VERSION 5.7 ;
  NOWIREEXTENSIONATPIN ON ;
  DIVIDERCHAR "/" ;
  BUSBITCHARS "[]" ;
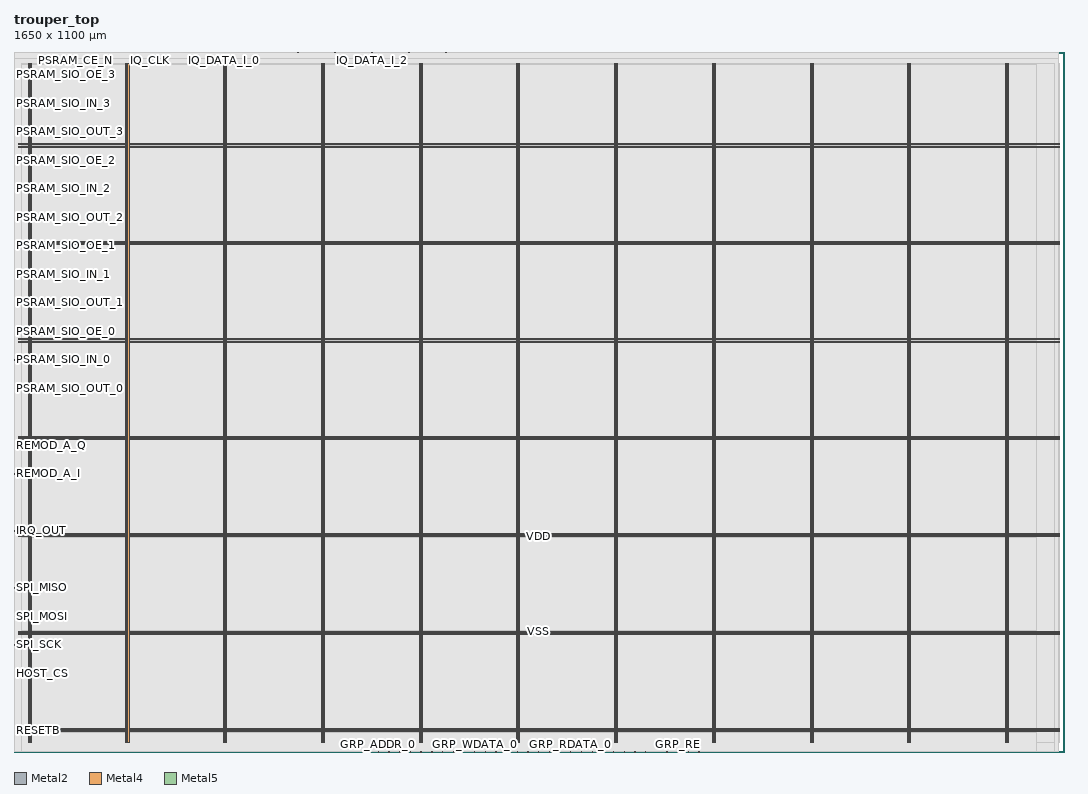
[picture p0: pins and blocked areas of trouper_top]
MACRO trouper_top
  CLASS BLOCK ;
  FOREIGN trouper_top ;
  ORIGIN 0.000 0.000 ;
  SIZE 1650.000 BY 1100.000 ;
  PIN GRP_ADDR_0
    DIRECTION INPUT ;
    USE SIGNAL ;
    ANTENNAGATEAREA 0.396000 ;
    PORT
      LAYER Metal2 ;
        RECT 572.320 0.000 572.880 0.560 ;
    END
  END GRP_ADDR_0
  PIN GRP_ADDR_1
    DIRECTION INPUT ;
    USE SIGNAL ;
    ANTENNAGATEAREA 0.396000 ;
    PORT
      LAYER Metal2 ;
        RECT 589.120 0.000 589.680 0.560 ;
    END
  END GRP_ADDR_1
  PIN GRP_ADDR_2
    DIRECTION INPUT ;
    USE SIGNAL ;
    ANTENNAGATEAREA 0.396000 ;
    PORT
      LAYER Metal2 ;
        RECT 605.920 0.000 606.480 0.560 ;
    END
  END GRP_ADDR_2
  PIN GRP_ADDR_3
    DIRECTION INPUT ;
    USE SIGNAL ;
    ANTENNAGATEAREA 0.396000 ;
    PORT
      LAYER Metal2 ;
        RECT 622.720 0.000 623.280 0.560 ;
    END
  END GRP_ADDR_3
  PIN GRP_ADDR_4
    DIRECTION INPUT ;
    USE SIGNAL ;
    ANTENNAGATEAREA 0.396000 ;
    PORT
      LAYER Metal2 ;
        RECT 639.520 0.000 640.080 0.560 ;
    END
  END GRP_ADDR_4
  PIN GRP_ADDR_5
    DIRECTION INPUT ;
    USE SIGNAL ;
    ANTENNAGATEAREA 0.396000 ;
    PORT
      LAYER Metal2 ;
        RECT 656.320 0.000 656.880 0.560 ;
    END
  END GRP_ADDR_5
  PIN GRP_ADDR_6
    DIRECTION INPUT ;
    USE SIGNAL ;
    ANTENNAGATEAREA 0.396000 ;
    PORT
      LAYER Metal2 ;
        RECT 673.120 0.000 673.680 0.560 ;
    END
  END GRP_ADDR_6
  PIN GRP_ADDR_7
    DIRECTION INPUT ;
    USE SIGNAL ;
    ANTENNAGATEAREA 0.396000 ;
    PORT
      LAYER Metal2 ;
        RECT 689.920 0.000 690.480 0.560 ;
    END
  END GRP_ADDR_7
  PIN GRP_RDATA_0
    DIRECTION OUTPUT ;
    USE SIGNAL ;
    ANTENNADIFFAREA 0.897600 ;
    PORT
      LAYER Metal2 ;
        RECT 874.720 0.000 875.280 0.560 ;
    END
  END GRP_RDATA_0
  PIN GRP_RDATA_1
    DIRECTION OUTPUT ;
    USE SIGNAL ;
    ANTENNADIFFAREA 0.897600 ;
    PORT
      LAYER Metal2 ;
        RECT 891.520 0.000 892.080 0.560 ;
    END
  END GRP_RDATA_1
  PIN GRP_RDATA_2
    DIRECTION OUTPUT ;
    USE SIGNAL ;
    ANTENNADIFFAREA 0.897600 ;
    PORT
      LAYER Metal2 ;
        RECT 908.320 0.000 908.880 0.560 ;
    END
  END GRP_RDATA_2
  PIN GRP_RDATA_3
    DIRECTION OUTPUT ;
    USE SIGNAL ;
    ANTENNADIFFAREA 0.897600 ;
    PORT
      LAYER Metal2 ;
        RECT 925.120 0.000 925.680 0.560 ;
    END
  END GRP_RDATA_3
  PIN GRP_RDATA_4
    DIRECTION OUTPUT ;
    USE SIGNAL ;
    ANTENNADIFFAREA 0.897600 ;
    PORT
      LAYER Metal2 ;
        RECT 941.920 0.000 942.480 0.560 ;
    END
  END GRP_RDATA_4
  PIN GRP_RDATA_5
    DIRECTION OUTPUT ;
    USE SIGNAL ;
    ANTENNADIFFAREA 0.897600 ;
    PORT
      LAYER Metal2 ;
        RECT 958.720 0.000 959.280 0.560 ;
    END
  END GRP_RDATA_5
  PIN GRP_RDATA_6
    DIRECTION OUTPUT ;
    USE SIGNAL ;
    ANTENNADIFFAREA 0.897600 ;
    PORT
      LAYER Metal2 ;
        RECT 975.520 0.000 976.080 0.560 ;
    END
  END GRP_RDATA_6
  PIN GRP_RDATA_7
    DIRECTION OUTPUT ;
    USE SIGNAL ;
    ANTENNADIFFAREA 0.897600 ;
    PORT
      LAYER Metal2 ;
        RECT 992.320 0.000 992.880 0.560 ;
    END
  END GRP_RDATA_7
  PIN GRP_RE
    DIRECTION INPUT ;
    USE SIGNAL ;
    ANTENNAGATEAREA 1.183000 ;
    PORT
      LAYER Metal2 ;
        RECT 1042.720 0.000 1043.280 0.560 ;
    END
  END GRP_RE
  PIN GRP_READY
    DIRECTION OUTPUT ;
    USE SIGNAL ;
    ANTENNADIFFAREA 0.897600 ;
    PORT
      LAYER Metal2 ;
        RECT 1059.520 0.000 1060.080 0.560 ;
    END
  END GRP_READY
  PIN GRP_WDATA_0
    DIRECTION INPUT ;
    USE SIGNAL ;
    ANTENNAGATEAREA 0.396000 ;
    PORT
      LAYER Metal2 ;
        RECT 723.520 0.000 724.080 0.560 ;
    END
  END GRP_WDATA_0
  PIN GRP_WDATA_1
    DIRECTION INPUT ;
    USE SIGNAL ;
    ANTENNAGATEAREA 0.396000 ;
    PORT
      LAYER Metal2 ;
        RECT 740.320 0.000 740.880 0.560 ;
    END
  END GRP_WDATA_1
  PIN GRP_WDATA_2
    DIRECTION INPUT ;
    USE SIGNAL ;
    ANTENNAGATEAREA 0.396000 ;
    PORT
      LAYER Metal2 ;
        RECT 757.120 0.000 757.680 0.560 ;
    END
  END GRP_WDATA_2
  PIN GRP_WDATA_3
    DIRECTION INPUT ;
    USE SIGNAL ;
    ANTENNAGATEAREA 0.396000 ;
    PORT
      LAYER Metal2 ;
        RECT 773.920 0.000 774.480 0.560 ;
    END
  END GRP_WDATA_3
  PIN GRP_WDATA_4
    DIRECTION INPUT ;
    USE SIGNAL ;
    ANTENNAGATEAREA 0.396000 ;
    PORT
      LAYER Metal2 ;
        RECT 790.720 0.000 791.280 0.560 ;
    END
  END GRP_WDATA_4
  PIN GRP_WDATA_5
    DIRECTION INPUT ;
    USE SIGNAL ;
    ANTENNAGATEAREA 0.396000 ;
    PORT
      LAYER Metal2 ;
        RECT 807.520 0.000 808.080 0.560 ;
    END
  END GRP_WDATA_5
  PIN GRP_WDATA_6
    DIRECTION INPUT ;
    USE SIGNAL ;
    ANTENNAGATEAREA 0.396000 ;
    PORT
      LAYER Metal2 ;
        RECT 824.320 0.000 824.880 0.560 ;
    END
  END GRP_WDATA_6
  PIN GRP_WDATA_7
    DIRECTION INPUT ;
    USE SIGNAL ;
    ANTENNAGATEAREA 0.396000 ;
    PORT
      LAYER Metal2 ;
        RECT 841.120 0.000 841.680 0.560 ;
    END
  END GRP_WDATA_7
  PIN GRP_WE
    DIRECTION INPUT ;
    USE SIGNAL ;
    ANTENNAGATEAREA 1.183000 ;
    PORT
      LAYER Metal2 ;
        RECT 1025.920 0.000 1026.480 0.560 ;
    END
  END GRP_WE
  PIN HOST_CS
    DIRECTION INPUT ;
    USE SIGNAL ;
    ANTENNAGATEAREA 2.369000 ;
    PORT
      LAYER Metal2 ;
        RECT 0.000 123.200 0.560 123.760 ;
    END
  END HOST_CS
  PIN IQ_CLK
    DIRECTION INPUT ;
    USE SIGNAL ;
    ANTENNAGATEAREA 9.476000 ;
    PORT
      LAYER Metal2 ;
        RECT 212.800 1099.440 213.360 1100.000 ;
    END
  END IQ_CLK
  PIN IQ_DATA_I_0
    DIRECTION INPUT ;
    USE SIGNAL ;
    ANTENNAGATEAREA 0.396000 ;
    PORT
      LAYER Metal2 ;
        RECT 329.280 1099.440 329.840 1100.000 ;
    END
  END IQ_DATA_I_0
  PIN IQ_DATA_I_1
    DIRECTION INPUT ;
    USE SIGNAL ;
    ANTENNAGATEAREA 0.396000 ;
    PORT
      LAYER Metal2 ;
        RECT 445.760 1099.440 446.320 1100.000 ;
    END
  END IQ_DATA_I_1
  PIN IQ_DATA_I_2
    DIRECTION INPUT ;
    USE SIGNAL ;
    ANTENNAGATEAREA 0.396000 ;
    PORT
      LAYER Metal2 ;
        RECT 562.240 1099.440 562.800 1100.000 ;
    END
  END IQ_DATA_I_2
  PIN IQ_DATA_I_3
    DIRECTION INPUT ;
    USE SIGNAL ;
    ANTENNAGATEAREA 0.396000 ;
    PORT
      LAYER Metal2 ;
        RECT 678.720 1099.440 679.280 1100.000 ;
    END
  END IQ_DATA_I_3
  PIN IQ_DATA_Q_0
    DIRECTION INPUT ;
    USE SIGNAL ;
    ANTENNAGATEAREA 0.396000 ;
    PORT
      LAYER Metal2 ;
        RECT 271.040 1099.440 271.600 1100.000 ;
    END
  END IQ_DATA_Q_0
  PIN IQ_DATA_Q_1
    DIRECTION INPUT ;
    USE SIGNAL ;
    ANTENNAGATEAREA 0.396000 ;
    PORT
      LAYER Metal2 ;
        RECT 387.520 1099.440 388.080 1100.000 ;
    END
  END IQ_DATA_Q_1
  PIN IQ_DATA_Q_2
    DIRECTION INPUT ;
    USE SIGNAL ;
    ANTENNAGATEAREA 0.396000 ;
    PORT
      LAYER Metal2 ;
        RECT 504.000 1099.440 504.560 1100.000 ;
    END
  END IQ_DATA_Q_2
  PIN IQ_DATA_Q_3
    DIRECTION INPUT ;
    USE SIGNAL ;
    ANTENNAGATEAREA 0.396000 ;
    PORT
      LAYER Metal2 ;
        RECT 620.480 1099.440 621.040 1100.000 ;
    END
  END IQ_DATA_Q_3
  PIN IRQ_GROUPER
    DIRECTION OUTPUT ;
    USE SIGNAL ;
    ANTENNADIFFAREA 0.897600 ;
    PORT
      LAYER Metal2 ;
        RECT 1076.320 0.000 1076.880 0.560 ;
    END
  END IRQ_GROUPER
  PIN IRQ_OUT
    DIRECTION OUTPUT ;
    USE SIGNAL ;
    ANTENNADIFFAREA 0.897600 ;
    PORT
      LAYER Metal2 ;
        RECT 0.000 347.200 0.560 347.760 ;
    END
  END IRQ_OUT
  PIN PSRAM_CE_N
    DIRECTION OUTPUT ;
    USE SIGNAL ;
    ANTENNADIFFAREA 0.897600 ;
    PORT
      LAYER Metal2 ;
        RECT 96.320 1099.440 96.880 1100.000 ;
    END
  END PSRAM_CE_N
  PIN PSRAM_SCK
    DIRECTION OUTPUT ;
    USE SIGNAL ;
    ANTENNADIFFAREA 0.897600 ;
    PORT
      LAYER Metal2 ;
        RECT 38.080 1099.440 38.640 1100.000 ;
    END
  END PSRAM_SCK
  PIN PSRAM_SIO_IN_0
    DIRECTION INPUT ;
    USE SIGNAL ;
    ANTENNAGATEAREA 0.396000 ;
    PORT
      LAYER Metal2 ;
        RECT 0.000 616.000 0.560 616.560 ;
    END
  END PSRAM_SIO_IN_0
  PIN PSRAM_SIO_IN_1
    DIRECTION INPUT ;
    USE SIGNAL ;
    ANTENNAGATEAREA 0.396000 ;
    PORT
      LAYER Metal2 ;
        RECT 0.000 750.400 0.560 750.960 ;
    END
  END PSRAM_SIO_IN_1
  PIN PSRAM_SIO_IN_2
    DIRECTION INPUT ;
    USE SIGNAL ;
    ANTENNAGATEAREA 0.396000 ;
    PORT
      LAYER Metal2 ;
        RECT 0.000 884.800 0.560 885.360 ;
    END
  END PSRAM_SIO_IN_2
  PIN PSRAM_SIO_IN_3
    DIRECTION INPUT ;
    USE SIGNAL ;
    ANTENNAGATEAREA 0.396000 ;
    PORT
      LAYER Metal2 ;
        RECT 0.000 1019.200 0.560 1019.760 ;
    END
  END PSRAM_SIO_IN_3
  PIN PSRAM_SIO_OE_0
    DIRECTION OUTPUT ;
    USE SIGNAL ;
    ANTENNADIFFAREA 0.897600 ;
    PORT
      LAYER Metal2 ;
        RECT 0.000 660.800 0.560 661.360 ;
    END
  END PSRAM_SIO_OE_0
  PIN PSRAM_SIO_OE_1
    DIRECTION OUTPUT ;
    USE SIGNAL ;
    ANTENNADIFFAREA 0.897600 ;
    PORT
      LAYER Metal2 ;
        RECT 0.000 795.200 0.560 795.760 ;
    END
  END PSRAM_SIO_OE_1
  PIN PSRAM_SIO_OE_2
    DIRECTION OUTPUT ;
    USE SIGNAL ;
    ANTENNADIFFAREA 0.897600 ;
    PORT
      LAYER Metal2 ;
        RECT 0.000 929.600 0.560 930.160 ;
    END
  END PSRAM_SIO_OE_2
  PIN PSRAM_SIO_OE_3
    DIRECTION OUTPUT ;
    USE SIGNAL ;
    ANTENNADIFFAREA 0.897600 ;
    PORT
      LAYER Metal2 ;
        RECT 0.000 1064.000 0.560 1064.560 ;
    END
  END PSRAM_SIO_OE_3
  PIN PSRAM_SIO_OUT_0
    DIRECTION OUTPUT ;
    USE SIGNAL ;
    ANTENNADIFFAREA 0.897600 ;
    PORT
      LAYER Metal2 ;
        RECT 0.000 571.200 0.560 571.760 ;
    END
  END PSRAM_SIO_OUT_0
  PIN PSRAM_SIO_OUT_1
    DIRECTION OUTPUT ;
    USE SIGNAL ;
    ANTENNADIFFAREA 0.897600 ;
    PORT
      LAYER Metal2 ;
        RECT 0.000 705.600 0.560 706.160 ;
    END
  END PSRAM_SIO_OUT_1
  PIN PSRAM_SIO_OUT_2
    DIRECTION OUTPUT ;
    USE SIGNAL ;
    ANTENNADIFFAREA 0.897600 ;
    PORT
      LAYER Metal2 ;
        RECT 0.000 840.000 0.560 840.560 ;
    END
  END PSRAM_SIO_OUT_2
  PIN PSRAM_SIO_OUT_3
    DIRECTION OUTPUT ;
    USE SIGNAL ;
    ANTENNADIFFAREA 0.897600 ;
    PORT
      LAYER Metal2 ;
        RECT 0.000 974.400 0.560 974.960 ;
    END
  END PSRAM_SIO_OUT_3
  PIN REMOD_A_I
    DIRECTION OUTPUT ;
    USE SIGNAL ;
    ANTENNADIFFAREA 0.897600 ;
    PORT
      LAYER Metal2 ;
        RECT 0.000 436.800 0.560 437.360 ;
    END
  END REMOD_A_I
  PIN REMOD_A_Q
    DIRECTION OUTPUT ;
    USE SIGNAL ;
    ANTENNADIFFAREA 0.897600 ;
    PORT
      LAYER Metal2 ;
        RECT 0.000 481.600 0.560 482.160 ;
    END
  END REMOD_A_Q
  PIN RESETB
    DIRECTION INPUT ;
    USE SIGNAL ;
    ANTENNAGATEAREA 5.924000 ;
    PORT
      LAYER Metal2 ;
        RECT 0.000 33.600 0.560 34.160 ;
    END
  END RESETB
  PIN SPI_MISO
    DIRECTION OUTPUT ;
    USE SIGNAL ;
    ANTENNADIFFAREA 0.897600 ;
    PORT
      LAYER Metal2 ;
        RECT 0.000 257.600 0.560 258.160 ;
    END
  END SPI_MISO
  PIN SPI_MOSI
    DIRECTION INPUT ;
    USE SIGNAL ;
    ANTENNAGATEAREA 0.396000 ;
    PORT
      LAYER Metal2 ;
        RECT 0.000 212.800 0.560 213.360 ;
    END
  END SPI_MOSI
  PIN SPI_SCK
    DIRECTION INPUT ;
    USE SIGNAL ;
    ANTENNAGATEAREA 2.369000 ;
    PORT
      LAYER Metal2 ;
        RECT 0.000 168.000 0.560 168.560 ;
    END
  END SPI_SCK
  PIN VDD
    DIRECTION INOUT ;
    USE POWER ;
    PORT
      LAYER Metal4 ;
        RECT 22.240 15.380 23.840 1082.220 ;
    END
    PORT
      LAYER Metal4 ;
        RECT 175.840 15.380 177.440 1082.220 ;
    END
    PORT
      LAYER Metal4 ;
        RECT 329.440 15.380 331.040 1082.220 ;
    END
    PORT
      LAYER Metal4 ;
        RECT 483.040 15.380 484.640 1082.220 ;
    END
    PORT
      LAYER Metal4 ;
        RECT 636.640 15.380 638.240 1082.220 ;
    END
    PORT
      LAYER Metal4 ;
        RECT 790.240 15.380 791.840 1082.220 ;
    END
    PORT
      LAYER Metal4 ;
        RECT 943.840 15.380 945.440 1082.220 ;
    END
    PORT
      LAYER Metal4 ;
        RECT 1097.440 15.380 1099.040 1082.220 ;
    END
    PORT
      LAYER Metal4 ;
        RECT 1251.040 15.380 1252.640 1082.220 ;
    END
    PORT
      LAYER Metal4 ;
        RECT 1404.640 15.380 1406.240 1082.220 ;
    END
    PORT
      LAYER Metal4 ;
        RECT 1558.240 15.380 1559.840 1082.220 ;
    END
    PORT
      LAYER Metal5 ;
        RECT 6.720 31.530 1643.040 33.130 ;
    END
    PORT
      LAYER Metal5 ;
        RECT 6.720 184.710 1643.040 186.310 ;
    END
    PORT
      LAYER Metal5 ;
        RECT 6.720 337.890 1643.040 339.490 ;
    END
    PORT
      LAYER Metal5 ;
        RECT 6.720 491.070 1643.040 492.670 ;
    END
    PORT
      LAYER Metal5 ;
        RECT 6.720 644.250 1643.040 645.850 ;
    END
    PORT
      LAYER Metal5 ;
        RECT 6.720 797.430 1643.040 799.030 ;
    END
    PORT
      LAYER Metal5 ;
        RECT 6.720 950.610 1643.040 952.210 ;
    END
  END VDD
  PIN VSS
    DIRECTION INOUT ;
    USE GROUND ;
    PORT
      LAYER Metal4 ;
        RECT 25.540 15.380 27.140 1082.220 ;
    END
    PORT
      LAYER Metal4 ;
        RECT 179.140 15.380 180.740 1082.220 ;
    END
    PORT
      LAYER Metal4 ;
        RECT 332.740 15.380 334.340 1082.220 ;
    END
    PORT
      LAYER Metal4 ;
        RECT 486.340 15.380 487.940 1082.220 ;
    END
    PORT
      LAYER Metal4 ;
        RECT 639.940 15.380 641.540 1082.220 ;
    END
    PORT
      LAYER Metal4 ;
        RECT 793.540 15.380 795.140 1082.220 ;
    END
    PORT
      LAYER Metal4 ;
        RECT 947.140 15.380 948.740 1082.220 ;
    END
    PORT
      LAYER Metal4 ;
        RECT 1100.740 15.380 1102.340 1082.220 ;
    END
    PORT
      LAYER Metal4 ;
        RECT 1254.340 15.380 1255.940 1082.220 ;
    END
    PORT
      LAYER Metal4 ;
        RECT 1407.940 15.380 1409.540 1082.220 ;
    END
    PORT
      LAYER Metal4 ;
        RECT 1561.540 15.380 1563.140 1082.220 ;
    END
    PORT
      LAYER Metal5 ;
        RECT 6.720 34.830 1643.040 36.430 ;
    END
    PORT
      LAYER Metal5 ;
        RECT 6.720 188.010 1643.040 189.610 ;
    END
    PORT
      LAYER Metal5 ;
        RECT 6.720 341.190 1643.040 342.790 ;
    END
    PORT
      LAYER Metal5 ;
        RECT 6.720 494.370 1643.040 495.970 ;
    END
    PORT
      LAYER Metal5 ;
        RECT 6.720 647.550 1643.040 649.150 ;
    END
    PORT
      LAYER Metal5 ;
        RECT 6.720 800.730 1643.040 802.330 ;
    END
    PORT
      LAYER Metal5 ;
        RECT 6.720 953.910 1643.040 955.510 ;
    END
  END VSS
  OBS
      LAYER Nwell ;
        RECT 6.290 15.250 1643.470 1082.350 ;
      LAYER Metal1 ;
        RECT 6.720 15.380 1643.040 1082.220 ;
      LAYER Metal2 ;
        RECT 0.140 1099.140 37.780 1099.860 ;
        RECT 38.940 1099.140 96.020 1099.860 ;
        RECT 97.180 1099.140 212.500 1099.860 ;
        RECT 213.660 1099.140 270.740 1099.860 ;
        RECT 271.900 1099.140 328.980 1099.860 ;
        RECT 330.140 1099.140 387.220 1099.860 ;
        RECT 388.380 1099.140 445.460 1099.860 ;
        RECT 446.620 1099.140 503.700 1099.860 ;
        RECT 504.860 1099.140 561.940 1099.860 ;
        RECT 563.100 1099.140 620.180 1099.860 ;
        RECT 621.340 1099.140 678.420 1099.860 ;
        RECT 679.580 1099.140 1641.780 1099.860 ;
        RECT 0.140 1064.860 1641.780 1099.140 ;
        RECT 0.860 1063.700 1641.780 1064.860 ;
        RECT 0.140 1020.060 1641.780 1063.700 ;
        RECT 0.860 1018.900 1641.780 1020.060 ;
        RECT 0.140 975.260 1641.780 1018.900 ;
        RECT 0.860 974.100 1641.780 975.260 ;
        RECT 0.140 930.460 1641.780 974.100 ;
        RECT 0.860 929.300 1641.780 930.460 ;
        RECT 0.140 885.660 1641.780 929.300 ;
        RECT 0.860 884.500 1641.780 885.660 ;
        RECT 0.140 840.860 1641.780 884.500 ;
        RECT 0.860 839.700 1641.780 840.860 ;
        RECT 0.140 796.060 1641.780 839.700 ;
        RECT 0.860 794.900 1641.780 796.060 ;
        RECT 0.140 751.260 1641.780 794.900 ;
        RECT 0.860 750.100 1641.780 751.260 ;
        RECT 0.140 706.460 1641.780 750.100 ;
        RECT 0.860 705.300 1641.780 706.460 ;
        RECT 0.140 661.660 1641.780 705.300 ;
        RECT 0.860 660.500 1641.780 661.660 ;
        RECT 0.140 616.860 1641.780 660.500 ;
        RECT 0.860 615.700 1641.780 616.860 ;
        RECT 0.140 572.060 1641.780 615.700 ;
        RECT 0.860 570.900 1641.780 572.060 ;
        RECT 0.140 482.460 1641.780 570.900 ;
        RECT 0.860 481.300 1641.780 482.460 ;
        RECT 0.140 437.660 1641.780 481.300 ;
        RECT 0.860 436.500 1641.780 437.660 ;
        RECT 0.140 348.060 1641.780 436.500 ;
        RECT 0.860 346.900 1641.780 348.060 ;
        RECT 0.140 258.460 1641.780 346.900 ;
        RECT 0.860 257.300 1641.780 258.460 ;
        RECT 0.140 213.660 1641.780 257.300 ;
        RECT 0.860 212.500 1641.780 213.660 ;
        RECT 0.140 168.860 1641.780 212.500 ;
        RECT 0.860 167.700 1641.780 168.860 ;
        RECT 0.140 124.060 1641.780 167.700 ;
        RECT 0.860 122.900 1641.780 124.060 ;
        RECT 0.140 34.460 1641.780 122.900 ;
        RECT 0.860 33.300 1641.780 34.460 ;
        RECT 0.140 0.860 1641.780 33.300 ;
        RECT 0.140 0.090 572.020 0.860 ;
        RECT 573.180 0.090 588.820 0.860 ;
        RECT 589.980 0.090 605.620 0.860 ;
        RECT 606.780 0.090 622.420 0.860 ;
        RECT 623.580 0.090 639.220 0.860 ;
        RECT 640.380 0.090 656.020 0.860 ;
        RECT 657.180 0.090 672.820 0.860 ;
        RECT 673.980 0.090 689.620 0.860 ;
        RECT 690.780 0.090 723.220 0.860 ;
        RECT 724.380 0.090 740.020 0.860 ;
        RECT 741.180 0.090 756.820 0.860 ;
        RECT 757.980 0.090 773.620 0.860 ;
        RECT 774.780 0.090 790.420 0.860 ;
        RECT 791.580 0.090 807.220 0.860 ;
        RECT 808.380 0.090 824.020 0.860 ;
        RECT 825.180 0.090 840.820 0.860 ;
        RECT 841.980 0.090 874.420 0.860 ;
        RECT 875.580 0.090 891.220 0.860 ;
        RECT 892.380 0.090 908.020 0.860 ;
        RECT 909.180 0.090 924.820 0.860 ;
        RECT 925.980 0.090 941.620 0.860 ;
        RECT 942.780 0.090 958.420 0.860 ;
        RECT 959.580 0.090 975.220 0.860 ;
        RECT 976.380 0.090 992.020 0.860 ;
        RECT 993.180 0.090 1025.620 0.860 ;
        RECT 1026.780 0.090 1042.420 0.860 ;
        RECT 1043.580 0.090 1059.220 0.860 ;
        RECT 1060.380 0.090 1076.020 0.860 ;
        RECT 1077.180 0.090 1641.780 0.860 ;
      LAYER Metal3 ;
        RECT 0.090 0.140 1641.830 1090.180 ;
      LAYER Metal4 ;
        RECT 12.460 15.080 21.940 1081.830 ;
        RECT 24.140 15.080 25.240 1081.830 ;
        RECT 27.440 15.080 175.540 1081.830 ;
        RECT 177.740 15.080 178.840 1081.830 ;
        RECT 181.040 15.080 329.140 1081.830 ;
        RECT 331.340 15.080 332.440 1081.830 ;
        RECT 334.640 15.080 482.740 1081.830 ;
        RECT 484.940 15.080 486.040 1081.830 ;
        RECT 488.240 15.080 636.340 1081.830 ;
        RECT 638.540 15.080 639.640 1081.830 ;
        RECT 641.840 15.080 789.940 1081.830 ;
        RECT 792.140 15.080 793.240 1081.830 ;
        RECT 795.440 15.080 943.540 1081.830 ;
        RECT 945.740 15.080 946.840 1081.830 ;
        RECT 949.040 15.080 1097.140 1081.830 ;
        RECT 1099.340 15.080 1100.440 1081.830 ;
        RECT 1102.640 15.080 1250.740 1081.830 ;
        RECT 1252.940 15.080 1254.040 1081.830 ;
        RECT 1256.240 15.080 1404.340 1081.830 ;
        RECT 1406.540 15.080 1407.640 1081.830 ;
        RECT 1409.840 15.080 1557.940 1081.830 ;
        RECT 1560.140 15.080 1561.240 1081.830 ;
        RECT 1563.440 15.080 1634.500 1081.830 ;
        RECT 12.460 0.090 1634.500 15.080 ;
      LAYER Metal5 ;
        RECT 12.380 956.110 1606.020 1079.770 ;
        RECT 12.380 952.810 1606.020 953.310 ;
        RECT 12.380 802.930 1606.020 950.010 ;
        RECT 12.380 799.630 1606.020 800.130 ;
        RECT 12.380 649.750 1606.020 796.830 ;
        RECT 12.380 646.450 1606.020 646.950 ;
        RECT 12.380 496.570 1606.020 643.650 ;
        RECT 12.380 493.270 1606.020 493.770 ;
        RECT 12.380 343.390 1606.020 490.470 ;
        RECT 12.380 340.090 1606.020 340.590 ;
        RECT 12.380 190.210 1606.020 337.290 ;
        RECT 12.380 186.910 1606.020 187.410 ;
        RECT 12.380 37.030 1606.020 184.110 ;
        RECT 12.380 33.730 1606.020 34.230 ;
        RECT 12.380 1.130 1606.020 30.930 ;
  END
END trouper_top
END LIBRARY

